One B-rep face of a CAD part: STEP entity #510.
In plain terms, the cylindrical face has radius 14 mm (diameter 28 mm), a partial arc.
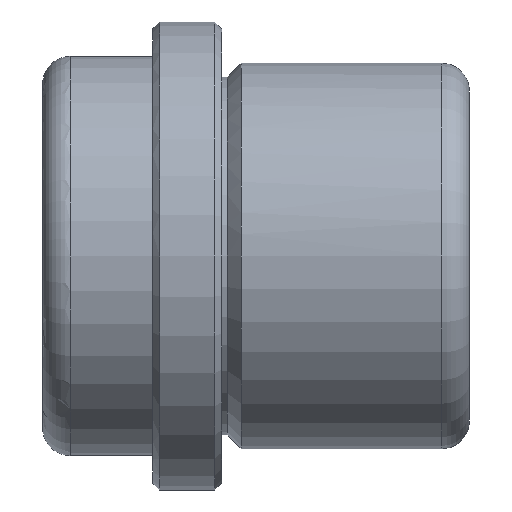
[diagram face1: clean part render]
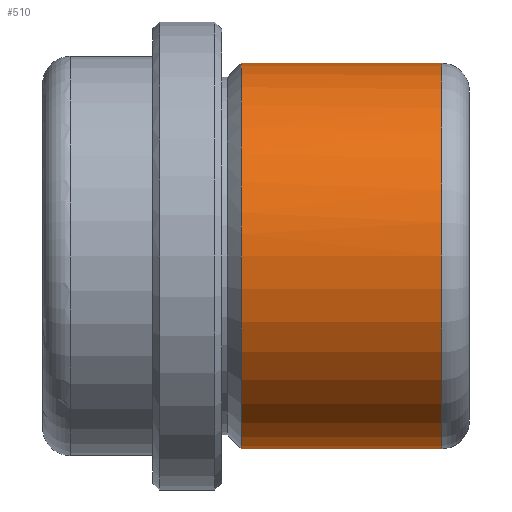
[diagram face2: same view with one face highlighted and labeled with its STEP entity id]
Its self-contained STEP definition (entity closure, numbers rounded to 3 decimals):
#293=CARTESIAN_POINT('Line Origine',(18.,0.,14.)) ;
#297=CARTESIAN_POINT('Vertex',(16.,0.,14.)) ;
#299=CARTESIAN_POINT('Vertex',(1.414,0.,14.)) ;
#313=CARTESIAN_POINT('Vertex',(16.,0.,-14.)) ;
#316=CARTESIAN_POINT('Line Origine',(18.,0.,-14.)) ;
#320=CARTESIAN_POINT('Vertex',(1.414,0.,-14.)) ;
#470=CARTESIAN_POINT('Axis2P3D Location',(18.,0.,0.)) ;
#475=CARTESIAN_POINT('Axis2P3D Location',(16.,0.,0.)) ;
#479=CARTESIAN_POINT('Vertex',(16.,-14.,0.)) ;
#482=CARTESIAN_POINT('Axis2P3D Location',(16.,0.,0.)) ;
#488=CARTESIAN_POINT('Control Point',(1.414,0.,14.)) ;
#489=CARTESIAN_POINT('Control Point',(1.414,-4.398,14.)) ;
#490=CARTESIAN_POINT('Control Point',(1.414,-8.801,12.278)) ;
#491=CARTESIAN_POINT('Control Point',(1.414,-12.278,8.801)) ;
#492=CARTESIAN_POINT('Control Point',(1.414,-14.,4.398)) ;
#493=CARTESIAN_POINT('Control Point',(1.414,-14.,0.)) ;
#494=CARTESIAN_POINT('Vertex',(1.414,-14.,0.)) ;
#497=CARTESIAN_POINT('Axis2P3D Location',(1.414,0.,0.)) ;
#294=DIRECTION('Vector Direction',(-1.,0.,0.)) ;
#317=DIRECTION('Vector Direction',(-1.,0.,0.)) ;
#471=DIRECTION('Axis2P3D Direction',(-1.,-0.,-0.)) ;
#472=DIRECTION('Axis2P3D XDirection',(0.,0.,-1.)) ;
#476=DIRECTION('Axis2P3D Direction',(-1.,-0.,-0.)) ;
#483=DIRECTION('Axis2P3D Direction',(-1.,-0.,-0.)) ;
#498=DIRECTION('Axis2P3D Direction',(-1.,-0.,-0.)) ;
#473=AXIS2_PLACEMENT_3D('Cylinder Axis2P3D',#470,#471,#472) ;
#477=AXIS2_PLACEMENT_3D('Circle Axis2P3D',#475,#476,$) ;
#484=AXIS2_PLACEMENT_3D('Circle Axis2P3D',#482,#483,$) ;
#499=AXIS2_PLACEMENT_3D('Circle Axis2P3D',#497,#498,$) ;
#503=ORIENTED_EDGE('',*,*,#322,.T.) ;
#504=ORIENTED_EDGE('',*,*,#481,.F.) ;
#505=ORIENTED_EDGE('',*,*,#486,.F.) ;
#506=ORIENTED_EDGE('',*,*,#301,.T.) ;
#507=ORIENTED_EDGE('',*,*,#496,.T.) ;
#508=ORIENTED_EDGE('',*,*,#501,.T.) ;
#295=VECTOR('Line Direction',#294,1.) ;
#318=VECTOR('Line Direction',#317,1.) ;
#510=ADVANCED_FACE('CF 631 18 x 31',(#509),#474,.T.) ;
#487=B_SPLINE_CURVE_WITH_KNOTS('',5,(#488,#489,#490,#491,#492,#493),.UNSPECIFIED.,.F.,.U.,(6,6),(-10.996,10.996),.UNSPECIFIED.) ;
#478=CIRCLE('generated circle',#477,14.) ;
#485=CIRCLE('generated circle',#484,14.) ;
#500=CIRCLE('generated circle',#499,14.) ;
#474=CYLINDRICAL_SURFACE('generated cylinder',#473,14.) ;
#301=EDGE_CURVE('',#298,#300,#296,.T.) ;
#322=EDGE_CURVE('',#321,#314,#319,.F.) ;
#481=EDGE_CURVE('',#480,#314,#478,.F.) ;
#486=EDGE_CURVE('',#298,#480,#485,.F.) ;
#496=EDGE_CURVE('',#300,#495,#487,.T.) ;
#501=EDGE_CURVE('',#495,#321,#500,.F.) ;
#502=EDGE_LOOP('',(#503,#504,#505,#506,#507,#508)) ;
#509=FACE_OUTER_BOUND('',#502,.T.) ;
#296=LINE('Line',#293,#295) ;
#319=LINE('Line',#316,#318) ;
#298=VERTEX_POINT('',#297) ;
#300=VERTEX_POINT('',#299) ;
#314=VERTEX_POINT('',#313) ;
#321=VERTEX_POINT('',#320) ;
#480=VERTEX_POINT('',#479) ;
#495=VERTEX_POINT('',#494) ;
